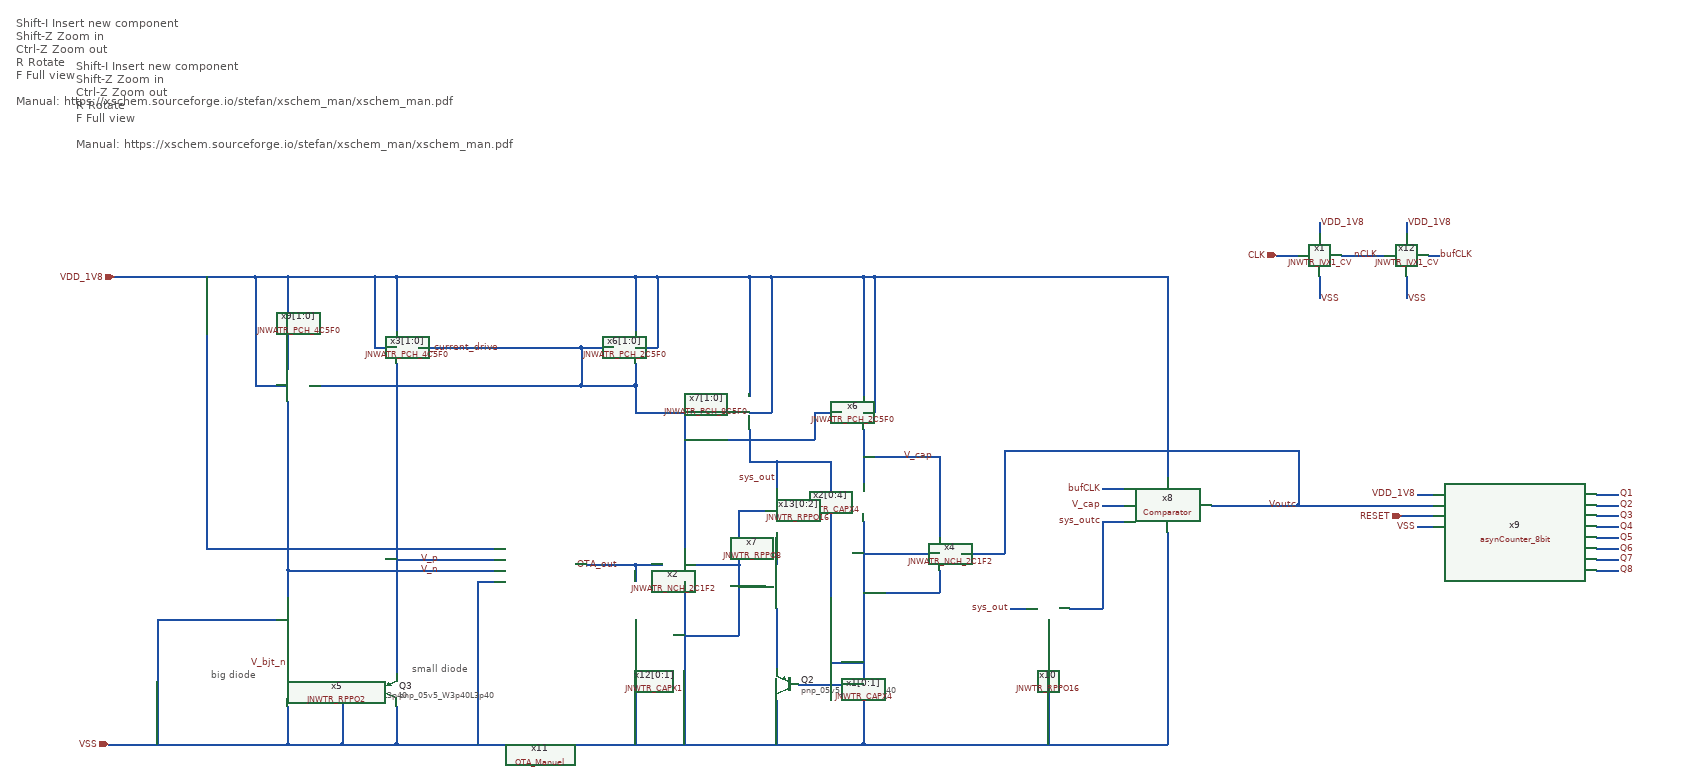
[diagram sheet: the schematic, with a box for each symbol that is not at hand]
v {xschem version=3.4.6 file_version=1.2}
G {}
K {}
V {}
S {}
E {}
T {Shift-I          Insert new component
Shift-Z         Zoom in
Ctrl-Z           Zoom out
R                 Rotate
F                 Full view

Manual: https://xschem.sourceforge.io/stefan/xschem_man/xschem_man.pdf
} -1500 -1380 0 0 0.6 0.6 {}
T {big diode
} -1140 -180 0 0 0.4 0.4 {}
T {small diode
} -770 -190 0 0 0.4 0.4 {}
T {Shift-I          Insert new component
Shift-Z         Zoom in
Ctrl-Z           Zoom out
R                 Rotate
F                 Full view

Manual: https://xschem.sourceforge.io/stefan/xschem_man/xschem_man.pdf
} -1390 -1300 0 0 0.6 0.6 {}
N 240 -390 300 -390 {lab=Voutc}
N 620 -390 620 -120 {lab=VSS}
N 330 -290 360 -290 {lab=sys_out}
N 820 -940 860 -940 {lab=CLK}
N 940 -940 960 -940 {lab=nCLK}
N 900 -1000 900 -980 {lab=VDD_1V8}
N 900 -900 900 -860 {lab=VSS}
N 500 -400 500 -290 {lab=sys_outc}
N 1100 -940 1120 -940 {lab=bufCLK}
N 960 -940 1020 -940 {lab=nCLK}
N 440 -290 500 -290 {lab=sys_outc}
N 400 -270 400 -120 {lab=VSS}
N 1060 -1000 1060 -980 {lab=VDD_1V8}
N 1060 -900 1060 -860 {lab=VSS}
N 620 -430 620 -390 {lab=VSS}
N 700 -480 860 -480 {lab=Voutc}
N 500 -510 540 -510 {lab=bufCLK}
N 500 -450 540 -450 {lab=sys_outc}
N 500 -480 540 -480 {lab=V_cap}
N 500 -450 500 -400 {lab=sys_outc}
N 860 -580 860 -480 {lab=Voutc}
N 320 -580 860 -580 {lab=Voutc}
N 1080 -460 1110 -460 {lab=RESET}
N 1080 -440 1110 -440 {lab=VSS}
N 1080 -480 1110 -480 {lab=Voutc}
N 1080 -500 1110 -500 {lab=VDD_1V8}
N 1050 -460 1080 -460 {lab=RESET}
N 860 -480 1080 -480 {lab=Voutc}
N 300 -390 320 -390 {lab=Voutc}
N 320 -580 320 -390 {lab=Voutc}
N -1000 -230 -1000 -170 {
lab=V_bjt_n}
N -900 -140 -840 -140 {
lab=VSS}
N -1000 -110 -1000 -40 {
lab=VSS}
N -800 -110 -800 -40 {
lab=VSS}
N -900 -140 -900 -40 {
lab=VSS}
N -900 -40 -800 -40 {
lab=VSS}
N -1120 -40 -1000 -40 {
lab=VSS}
N -1000 -360 -1000 -310 {
lab=V_n}
N -800 -40 -720 -40 {
lab=VSS}
N -360 -370 -310 -370 {
lab=OTA_out}
N -270 -370 -230 -370 {
lab=VSS}
N -270 -650 -270 -400 {
lab=V_current_drive}
N -150 -620 -150 -560 {
lab=sys_out}
N -150 -650 -110 -650 {
lab=VDD_1V8}
N -150 -900 -110 -900 {
lab=VDD_1V8}
N -360 -650 -190 -650 {
lab=V_current_drive}
N -150 -900 -150 -680 {
lab=VDD_1V8}
N -110 -900 -110 -650 {
lab=VDD_1V8}
N -1120 -270 -1020 -270 {
lab=VSS}
N -1240 -270 -1240 -40 {
lab=VSS}
N -360 -270 -360 -220 {
lab=VSS}
N -360 -370 -360 -340 {
lab=OTA_out}
N -960 -140 -900 -140 {
lab=VSS}
N -1000 -40 -900 -40 {
lab=VSS}
N -270 -340 -270 -260 {
lab=VSS}
N -1150 -40 -1120 -40 {
lab=VSS}
N -720 -380 -690 -380 {
lab=V_p}
N -720 -360 -690 -360 {
lab=V_n}
N -1000 -360 -720 -360 {
lab=V_n}
N -800 -380 -720 -380 {
lab=V_p}
N -100 -290 -100 -240 {
lab=#net1}
N -720 -40 -230 -40 {
lab=VSS}
N -360 -220 -360 -40 {
lab=VSS}
N -1330 -40 -1150 -40 {lab=VSS}
N -1240 -270 -1120 -270 {lab=VSS}
N -1150 -400 -690 -400 {lab=VDD_1V8}
N -450 -370 -360 -370 {lab=OTA_out}
N -690 -400 -620 -400 {lab=VDD_1V8}
N -690 -380 -620 -380 {lab=V_p}
N -690 -360 -620 -360 {lab=V_n}
N -650 -340 -630 -340 {lab=VSS}
N -650 -340 -650 -40 {lab=VSS}
N -630 -340 -620 -340 {lab=VSS}
N -150 -560 -100 -560 {lab=sys_out}
N -100 -240 -100 -220 {lab=#net1}
N 60 -450 60 -40 {lab=VSS}
N -230 -40 60 -40 {lab=VSS}
N 60 -620 60 -520 {lab=V_cap}
N -270 -600 -30 -600 {lab=V_current_drive}
N -30 -650 -30 -600 {lab=V_current_drive}
N -30 -650 20 -650 {lab=V_current_drive}
N -110 -900 60 -900 {lab=VDD_1V8}
N 60 -900 60 -680 {lab=VDD_1V8}
N 60 -650 80 -650 {lab=VDD_1V8}
N 80 -900 80 -650 {lab=VDD_1V8}
N 60 -900 80 -900 {lab=VDD_1V8}
N 60 -570 200 -570 {lab=V_cap}
N 200 -570 200 -420 {lab=V_cap}
N 60 -390 200 -390 {lab=VSS}
N 200 -360 200 -320 {lab=VSS}
N 60 -320 200 -320 {lab=VSS}
N -1000 -460 -1000 -360 {lab=V_n}
N 80 -900 610 -900 {lab=VDD_1V8}
N 60 -40 610 -40 {lab=VSS}
N -100 -220 -100 -180 {lab=#net1}
N -60 -150 50 -150 {lab=VSS}
N 50 -150 60 -150 {lab=VSS}
N -100 -120 -100 -40 {lab=VSS}
N -1000 -670 -1000 -460 {lab=V_n}
N 0 -390 0 -310 {lab=sys_out}
N 0 -240 0 -190 {lab=VSS}
N 0 -190 60 -190 {lab=VSS}
N -100 -560 -100 -510 {lab=sys_out}
N 0 -560 0 -390 {lab=sys_out}
N -100 -560 0 -560 {lab=sys_out}
N -270 -260 -270 -40 {lab=VSS}
N -170 -280 -170 -240 {lab=VSS}
N -270 -240 -170 -240 {lab=VSS}
N -170 -330 -120 -330 {lab=VSS}
N -100 -430 -100 -370 {lab=#net2}
N -230 -370 -170 -370 {lab=VSS}
N -170 -370 -170 -280 {lab=VSS}
N -170 -470 -120 -470 {lab=VSS}
N -170 -470 -170 -370 {lab=VSS}
N 620 -120 620 -40 {lab=VSS}
N 610 -40 620 -40 {lab=VSS}
N 400 -120 400 -40 {lab=VSS}
N 610 -900 620 -900 {lab=VDD_1V8}
N 620 -900 620 -560 {lab=VDD_1V8}
N 620 -560 620 -530 {lab=VDD_1V8}
N -1000 -900 -840 -900 {
lab=VDD_1V8}
N -800 -900 -360 -900 {
lab=VDD_1V8}
N -360 -900 -320 -900 {
lab=VDD_1V8}
N -360 -900 -360 -800 {
lab=VDD_1V8}
N -360 -770 -320 -770 {
lab=VDD_1V8}
N -320 -900 -320 -770 {
lab=VDD_1V8}
N -460 -770 -460 -700 {
lab=V_current_drive}
N -1150 -900 -1150 -400 {
lab=VDD_1V8}
N -1320 -900 -1060 -900 {
lab=VDD_1V8}
N -800 -900 -800 -800 {
lab=VDD_1V8}
N -840 -900 -840 -770 {
lab=VDD_1V8}
N -460 -770 -400 -770 {
lab=V_current_drive}
N -840 -770 -800 -770 {
lab=VDD_1V8}
N -320 -900 -150 -900 {
lab=VDD_1V8}
N -460 -700 -360 -700 {
lab=V_current_drive}
N -1060 -700 -1000 -700 {
lab=VDD_1V8}
N -1060 -900 -1060 -700 {
lab=VDD_1V8}
N -1000 -900 -1000 -730 {
lab=VDD_1V8}
N -760 -770 -460 -770 {
lab=V_current_drive}
N -960 -700 -460 -700 {
lab=V_current_drive}
N -360 -740 -360 -700 {
lab=V_current_drive}
N -840 -900 -800 -900 {
lab=VDD_1V8}
N -360 -700 -360 -650 {
lab=V_current_drive}
N -1060 -900 -1000 -900 {
lab=VDD_1V8}
N -800 -740 -800 -170 {
lab=V_p}
N 1410 -500 1450 -500 {lab=Q1}
N 1410 -480 1450 -480 {lab=Q2}
N 1410 -460 1450 -460 {lab=Q3}
N 1410 -440 1450 -440 {lab=Q4}
N 1410 -420 1450 -420 {lab=Q5}
N 1410 -400 1450 -400 {lab=Q5}
N 1410 -380 1450 -380 {lab=Q7}
N 1410 -360 1450 -360 {lab=Q8}
C {devices/ipin.sym} 1050 -460 0 0 {name=p5 lab=RESET
}
C {JNW_GR05_SKY130A/Comparator.sym} 620 -480 0 0 {name=x8}
C {devices/lab_wire.sym} 500 -480 0 0 {name=p18 sig_type=std_logic lab=V_cap}
C {devices/lab_wire.sym} 330 -290 0 0 {name=p19 sig_type=std_logic lab=sys_out}
C {JNW_TR_SKY130A/JNWTR_IVX1_CV.sym} 860 -940 0 0 {name=x1 }
C {devices/lab_wire.sym} 960 -940 0 1 {name=p6 sig_type=std_logic lab=nCLK}
C {devices/lab_wire.sym} 900 -1000 0 1 {name=p21 sig_type=std_logic lab=VDD_1V8
}
C {devices/lab_wire.sym} 900 -860 0 1 {name=p22 sig_type=std_logic lab=VSS
}
C {devices/lab_wire.sym} 1120 -940 0 1 {name=p27 sig_type=std_logic lab=bufCLK}
C {devices/lab_wire.sym} 500 -510 0 0 {name=p9 sig_type=std_logic lab=bufCLK}
C {JNW_TR_SKY130A/JNWTR_RPPO16.sym} 360 -290 0 0 {name=x10}
C {JNW_TR_SKY130A/JNWTR_IVX1_CV.sym} 1020 -940 0 0 {name=x12 }
C {devices/lab_wire.sym} 1060 -1000 0 1 {name=p26 sig_type=std_logic lab=VDD_1V8
}
C {devices/lab_wire.sym} 1060 -860 0 1 {name=p28 sig_type=std_logic lab=VSS
}
C {devices/lab_wire.sym} 860 -480 0 0 {name=p2 sig_type=std_logic lab=Voutc}
C {devices/ipin.sym} 820 -940 0 0 {name=p14 lab=CLK
}
C {devices/lab_wire.sym} 500 -450 0 0 {name=p3 sig_type=std_logic lab=sys_outc}
C {devices/lab_wire.sym} 1080 -440 0 0 {name=p4 sig_type=std_logic lab=VSS
}
C {devices/lab_pin.sym} 1080 -500 0 0 {name=p20 sig_type=std_logic lab=VDD_1V8
}
C {devices/lab_pin.sym} 1450 -400 0 1 {name=p16 sig_type=std_logic lab=Q6
}
C {devices/lab_pin.sym} 1450 -500 0 1 {name=p23 sig_type=std_logic lab=Q1
}
C {devices/lab_pin.sym} 1450 -460 0 1 {name=p24 sig_type=std_logic lab=Q3}
C {devices/lab_pin.sym} 1450 -440 0 1 {name=p25 sig_type=std_logic lab=Q4}
C {devices/ipin.sym} -1320 -900 0 0 {name=p1 lab=VDD_1V8}
C {devices/ipin.sym} -1330 -40 0 0 {name=p8 lab=VSS}
C {JNW_ATR_SKY130A/JNWATR_PCH_8C5F0.sym} -190 -650 0 0 {name=x7[1:0]}
C {sky130_fd_pr/pnp_05v5.sym} -820 -140 0 0 {name=Q3
model=pnp_05v5_W3p40L3p40
m=1
spiceprefix=X
}
C {sky130_fd_pr/pnp_05v5.sym} -980 -140 0 1 {name=Q1
model=pnp_05v5_W3p40L3p40
m=5
spiceprefix=X
}
C {devices/lab_wire.sym} -390 -370 0 0 {name=p10 sig_type=std_logic lab=OTA_out}
C {devices/lab_wire.sym} -720 -380 0 0 {name=p12 sig_type=std_logic lab=V_p}
C {devices/lab_wire.sym} -720 -360 0 0 {name=p13 sig_type=std_logic lab=V_n}
C {JNW_GR05_SKY130A/OTA_Manuel.sym} -470 -370 0 0 {name=x11}
C {devices/lab_wire.sym} -1000 -190 0 0 {name=p15 sig_type=std_logic lab=V_bjt_n}
C {JNW_ATR_SKY130A/JNWATR_NCH_2C1F2.sym} -310 -370 0 0 {name=x2 }
C {JNW_TR_SKY130A/JNWTR_RPPO2.sym} -1000 -310 1 0 {name=x5}
C {JNW_ATR_SKY130A/JNWATR_PCH_2C5F0.sym} 20 -650 0 0 {name=x6}
C {JNW_ATR_SKY130A/JNWATR_NCH_2C1F2.sym} 240 -390 0 1 {name=x4 }
C {JNW_TR_SKY130A/JNWTR_CAPX4.sym} 60 -460 0 0 {name=x2[0:4]}
C {devices/lab_wire.sym} -100 -530 0 0 {name=p7 sig_type=std_logic lab=sys_out}
C {devices/lab_wire.sym} 190 -570 0 0 {name=p17 sig_type=std_logic lab=V_cap}
C {JNW_TR_SKY130A/JNWTR_CAPX1.sym} -360 -280 0 0 {name=x12[0:1]}
C {sky130_fd_pr/pnp_05v5.sym} -80 -150 0 1 {name=Q2
model=pnp_05v5_W3p40L3p40
m=1
spiceprefix=X
}
C {JNW_TR_SKY130A/JNWTR_CAPX4.sym} 0 -250 0 0 {name=x1[0:1]}
C {JNW_TR_SKY130A/JNWTR_RPPO8.sym} -100 -370 1 0 {name=x7}
C {JNW_TR_SKY130A/JNWTR_RPPO16.sym} -100 -510 1 0 {name=x13[0:2]}
C {JNW_ATR_SKY130A/JNWATR_PCH_4C5F0.sym} -960 -700 0 1 {name=x9[1:0]}
C {JNW_ATR_SKY130A/JNWATR_PCH_2C5F0.sym} -400 -770 0 0 {name=x6[1:0]}
C {devices/lab_wire.sym} -610 -770 0 0 {name=p11 sig_type=std_logic lab=V_current_drive}
C {JNW_ATR_SKY130A/JNWATR_PCH_4C5F0.sym} -760 -770 0 1 {name=x3[1:0]}
C {JNW_GR05_SKY130A/asynCounter_8bit.sym} 1260 -430 0 0 {name=x9}
C {devices/lab_pin.sym} 1450 -360 0 1 {name=p29 sig_type=std_logic lab=Q8

}
C {devices/lab_pin.sym} 1450 -420 0 1 {name=p30 sig_type=std_logic lab=Q5
}
C {devices/lab_pin.sym} 1450 -480 0 1 {name=p31 sig_type=std_logic lab=Q2}
C {devices/lab_pin.sym} 1450 -380 0 1 {name=p32 sig_type=std_logic lab=Q7}
